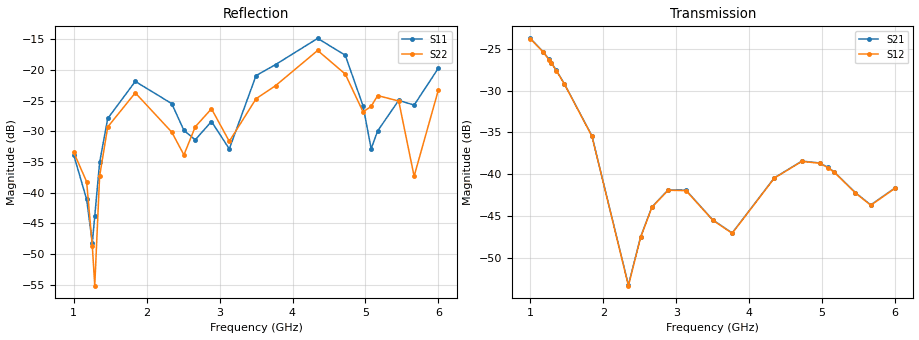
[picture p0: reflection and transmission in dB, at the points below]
!Agilent Technologies,E8364B,MY43040528,A.07.50.67
!Agilent E8364B: A.07.50.67
!Date: Sunday, March 01, 2026 16:47:54
!Correction: S11(Full 2 Port(1,2))
!S21(Full 2 Port(1,2))
!S12(Full 2 Port(1,2))
!S22(Full 2 Port(1,2))
!S2P File: Measurements: S11, S21, S12, S22:
# Hz S  dB  R 50
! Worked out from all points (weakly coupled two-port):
!   451 points, 1 GHz to 6 GHz, reference 50 ohm
!   highest |S21| = -23.77 dB at 1 GHz (marker M1); lowest = -53.2 dB at 2.344 GHz (marker M2)
!   lowest |S11| = -48.2 dB at 1.256 GHz (marker M3), VSWR 1.01, Z = 49.9 + j0.372 ohm
!   |S11| at or under -10 dB: start of sweep to end of sweep
!   |S22| runs from -58.3 to -16.8 dB; largest |S21 - S12| = 0.00029
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1e9  -33.84 31.7  -23.77 153.1  -23.81 153.1  -33.41 -2.6
1.177778e9  -41.10 49.7  -25.39 51.4  -25.43 51.4  -38.23 -5.4
1.255556e9  -48.16 107.4  -26.27 7.2  -26.31 7.2  -48.70 -9.6
1.288889e9  -43.85 155.8  -26.68 -11.7  -26.73 -11.6  -55.15 99.5
1.355556e9  -35.08 167.6  -27.58 -49.0  -27.61 -48.9  -37.30 117.0
1.466667e9  -27.92 147.3  -29.20 -110.1  -29.23 -110.1  -29.30 89.2
1.844444e9  -21.88 75.6  -35.42 47.6  -35.45 47.7  -23.74 -4.9
2.344444e9  -25.50 13.4  -53.23 -150.7  -53.29 -150.4  -30.14 -82.6
2.511111e9  -29.85 6.4  -47.48 178.8  -47.53 178.9  -33.85 -66.1
2.666667e9  -31.39 35.2  -43.90 104.4  -43.93 104.4  -29.27 -58.2
2.888889e9  -28.41 29.2  -41.85 -11.9  -41.90 -11.8  -26.34 -101.8
3.133333e9  -32.88 52.1  -41.89 -141.8  -41.94 -141.8  -31.64 -133.2
3.5e9  -20.93 47.2  -45.43 37.1  -45.47 37.1  -24.70 -127.8
3.766667e9  -19.15 21.7  -47.00 -66.1  -47.04 -66.2  -22.58 -155.6
4.344444e9  -14.87 -44.8  -40.42 22.7  -40.45 22.7  -16.84 111.4
4.722222e9  -17.61 -103.3  -38.42 172.5  -38.45 172.5  -20.68 42.4
4.966667e9  -25.86 -133.9  -38.64 29.6  -38.68 29.6  -26.84 34.3
5.077778e9  -32.85 -104.5  -39.15 -36.7  -39.20 -36.6  -25.95 45.1
5.166667e9  -29.95 -61.5  -39.72 -90.4  -39.76 -90.4  -24.19 38.6
5.455556e9  -24.96 -78.6  -42.18 86.0  -42.22 86.0  -25.07 -20.4
5.666667e9  -25.74 -64.9  -43.65 -63.0  -43.69 -63.0  -37.32 -8.1
6e9  -19.71 -73.4  -41.61 59.9  -41.66 59.9  -23.25 -0.9
